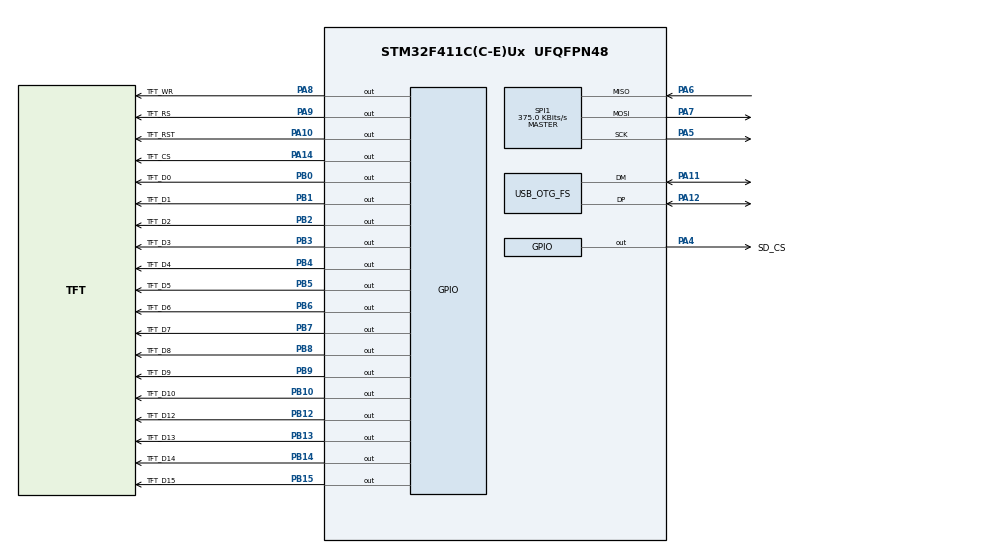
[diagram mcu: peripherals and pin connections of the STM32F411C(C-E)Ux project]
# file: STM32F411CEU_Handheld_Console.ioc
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ADC1.Channel-0\#ChannelRegularConversion=ADC_CHANNEL_VREFINT
ADC1.ClockPrescaler=ADC_CLOCK_SYNC_PCLK_DIV4
ADC1.NbrOfConversionFlag=1
ADC1.Rank-0\#ChannelRegularConversion=1
ADC1.SamplingTime-0\#ChannelRegularConversion=ADC_SAMPLETIME_3CYCLES
ADC1.master=1
Mcu.Family=STM32F4
Mcu.Name=STM32F411C(C-E)Ux
Mcu.Package=UFQFPN48
NVIC.OTG_FS_IRQn=true\:0\:0\:false\:false\:true\:false\:true\:true
NVIC.PriorityGroup=NVIC_PRIORITYGROUP_4
PA10.GPIO_Label=TFT_RST
PA10.GPIO_PuPd=GPIO_PULLDOWN
PA10.GPIO_Speed=GPIO_SPEED_FREQ_VERY_HIGH
PA10.Signal=GPIO_Output
PA11.Mode=Device_Only
PA11.Signal=USB_OTG_FS_DM
PA12.Mode=Device_Only
PA12.Signal=USB_OTG_FS_DP
PA14.GPIO_Label=TFT_CS
PA14.GPIO_PuPd=GPIO_PULLDOWN
PA14.GPIO_Speed=GPIO_SPEED_FREQ_VERY_HIGH
PA14.Signal=GPIO_Output
PA4.GPIO_Label=SD_CS
PA4.GPIO_Speed=GPIO_SPEED_FREQ_LOW
PA4.PinState=GPIO_PIN_RESET
PA4.Signal=GPIO_Output
PA5.GPIO_PuPd=GPIO_NOPULL
PA5.Mode=Full_Duplex_Master
PA5.Signal=SPI1_SCK
PA6.GPIO_PuPd=GPIO_NOPULL
PA6.Mode=Full_Duplex_Master
PA6.Signal=SPI1_MISO
PA7.GPIO_PuPd=GPIO_NOPULL
PA7.Mode=Full_Duplex_Master
PA7.Signal=SPI1_MOSI
PA8.GPIO_Label=TFT_WR
PA8.GPIO_PuPd=GPIO_PULLDOWN
PA8.GPIO_Speed=GPIO_SPEED_FREQ_VERY_HIGH
PA8.Signal=GPIO_Output
PA9.GPIO_Label=TFT_RS
PA9.GPIO_PuPd=GPIO_PULLDOWN
PA9.GPIO_Speed=GPIO_SPEED_FREQ_VERY_HIGH
PA9.Signal=GPIO_Output
PB0.GPIO_Label=TFT_D0
PB0.GPIO_PuPd=GPIO_PULLDOWN
PB0.GPIO_Speed=GPIO_SPEED_FREQ_VERY_HIGH
PB0.Signal=GPIO_Output
PB1.GPIO_Label=TFT_D1
PB1.GPIO_PuPd=GPIO_PULLDOWN
PB1.GPIO_Speed=GPIO_SPEED_FREQ_VERY_HIGH
PB1.Signal=GPIO_Output
PB10.GPIO_Label=TFT_D10
PB10.GPIO_PuPd=GPIO_PULLDOWN
PB10.GPIO_Speed=GPIO_SPEED_FREQ_VERY_HIGH
PB10.Signal=GPIO_Output
PB12.GPIO_Label=TFT_D12
PB12.GPIO_PuPd=GPIO_PULLDOWN
PB12.GPIO_Speed=GPIO_SPEED_FREQ_VERY_HIGH
PB12.Signal=GPIO_Output
PB13.GPIO_Label=TFT_D13
PB13.GPIO_PuPd=GPIO_PULLDOWN
PB13.GPIO_Speed=GPIO_SPEED_FREQ_VERY_HIGH
PB13.Signal=GPIO_Output
PB14.GPIO_Label=TFT_D14
PB14.GPIO_PuPd=GPIO_PULLDOWN
PB14.GPIO_Speed=GPIO_SPEED_FREQ_VERY_HIGH
PB14.Signal=GPIO_Output
PB15.GPIO_Label=TFT_D15
PB15.GPIO_PuPd=GPIO_PULLDOWN
PB15.GPIO_Speed=GPIO_SPEED_FREQ_VERY_HIGH
PB15.Signal=GPIO_Output
PB2.GPIO_Label=TFT_D2
PB2.GPIO_PuPd=GPIO_PULLDOWN
PB2.GPIO_Speed=GPIO_SPEED_FREQ_VERY_HIGH
PB2.Signal=GPIO_Output
PB3.GPIO_Label=TFT_D3
PB3.GPIO_PuPd=GPIO_PULLDOWN
PB3.GPIO_Speed=GPIO_SPEED_FREQ_VERY_HIGH
PB3.Signal=GPIO_Output
PB4.GPIO_Label=TFT_D4
PB4.GPIO_PuPd=GPIO_PULLDOWN
PB4.GPIO_Speed=GPIO_SPEED_FREQ_VERY_HIGH
PB4.Signal=GPIO_Output
PB5.GPIO_Label=TFT_D5
PB5.GPIO_PuPd=GPIO_PULLDOWN
PB5.GPIO_Speed=GPIO_SPEED_FREQ_VERY_HIGH
PB5.Signal=GPIO_Output
PB6.GPIO_Label=TFT_D6
PB6.GPIO_PuPd=GPIO_PULLDOWN
PB6.GPIO_Speed=GPIO_SPEED_FREQ_VERY_HIGH
PB6.Signal=GPIO_Output
PB7.GPIO_Label=TFT_D7
PB7.GPIO_PuPd=GPIO_PULLDOWN
PB7.GPIO_Speed=GPIO_SPEED_FREQ_VERY_HIGH
PB7.Signal=GPIO_Output
PB8.GPIO_Label=TFT_D8
PB8.GPIO_PuPd=GPIO_PULLDOWN
PB8.GPIO_Speed=GPIO_SPEED_FREQ_VERY_HIGH
PB8.Signal=GPIO_Output
PB9.GPIO_Label=TFT_D9
PB9.GPIO_PuPd=GPIO_PULLDOWN
PB9.GPIO_Speed=GPIO_SPEED_FREQ_VERY_HIGH
PB9.Signal=GPIO_Output
PH0\ -\ OSC_IN.Mode=HSE-External-Oscillator
PH0\ -\ OSC_IN.Signal=RCC_OSC_IN
PH1\ -\ OSC_OUT.Mode=HSE-External-Oscillator
PH1\ -\ OSC_OUT.Signal=RCC_OSC_OUT
ProjectManager.HeapSize=0x200
ProjectManager.StackSize=0x400
ProjectManager.TargetToolchain=STM32CubeIDE
RCC.48MHZClocksFreq_Value=48000000
RCC.AHBFreq_Value=96000000
RCC.APB1CLKDivider=RCC_HCLK_DIV2
RCC.APB1Freq_Value=48000000
RCC.APB1TimFreq_Value=96000000
RCC.APB2Freq_Value=96000000
RCC.APB2TimFreq_Value=96000000
RCC.CortexFreq_Value=96000000
RCC.HCLKFreq_Value=96000000
RCC.HSE_VALUE=25000000
RCC.HSI_VALUE=16000000
RCC.LSE_VALUE=32768
RCC.PLLM=25
RCC.SYSCLKFreq_VALUE=96000000
RCC.SYSCLKSource=RCC_SYSCLKSOURCE_PLLCLK
RCC.VCOOutputFreq_Value=192000000
SPI1.BaudRatePrescaler=SPI_BAUDRATEPRESCALER_256
SPI1.CLKPolarity=SPI_POLARITY_LOW
SPI1.CRCCalculation=SPI_CRCCALCULATION_DISABLE
SPI1.CalculateBaudRate=375.0 KBits/s
SPI1.Direction=SPI_DIRECTION_2LINES
SPI1.FirstBit=SPI_FIRSTBIT_MSB
SPI1.Mode=SPI_MODE_MASTER
SPI1.VirtualType=VM_MASTER
USB_DEVICE.CLASS_NAME_FS=CDC
USB_DEVICE.VirtualMode=Cdc
USB_DEVICE.VirtualModeFS=Cdc_FS
USB_OTG_FS.VirtualMode=Device_Only
VP_ADC1_Vref_Input.Mode=IN-Vrefint
VP_FATFS_VS_Generic.Mode=User_defined
VP_USB_DEVICE_VS_USB_DEVICE_CDC_FS.Mode=CDC_FS
board=custom

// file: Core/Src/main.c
/* USER CODE BEGIN Header */
/**
 ******************************************************************************
 * @file           : main.c
 * @brief          : Main program body
 ******************************************************************************
 * @attention
 *
 * Copyright (c) 2023 STMicroelectronics.
 * All rights reserved.
 *
 * This software is licensed under terms that can be found in the LICENSE file
 * in the root directory of this software component.
 * If no LICENSE file comes with this software, it is provided AS-IS.
 *
 ******************************************************************************
 */
/* USER CODE END Header */
#include "main.h"
#include "fatfs.h"

/* USER CODE BEGIN Includes */
#include "../STM32_Handheld_Console/STM32_Handheld_Console.h"
/* USER CODE END Includes */

ADC_HandleTypeDef hadc1;

SPI_HandleTypeDef hspi1;

void SystemClock_Config(void);
static void MX_GPIO_Init(void);
static void MX_SPI1_Init(void);
static void MX_ADC1_Init(void);

int main(void)
{

  /* MCU Configuration--------------------------------------------------------*/

  /* Reset of all peripherals, Initializes the Flash interface and the Systick. */
  HAL_Init();

  /* Configure the system clock */
  SystemClock_Config();

  /* Initialize all configured peripherals */
  MX_GPIO_Init();
  MX_SPI1_Init();
  MX_FATFS_Init();
  MX_ADC1_Init();
  /* USER CODE BEGIN 2 */
  system_main();
  /* USER CODE END 2 */

  /* Infinite loop */
	while (1)
	{

	}
}

void SystemClock_Config(void)
{
  RCC_OscInitTypeDef RCC_OscInitStruct = {0};
  RCC_ClkInitTypeDef RCC_ClkInitStruct = {0};

  /** Configure the main internal regulator output voltage
  */
  __HAL_RCC_PWR_CLK_ENABLE();
  __HAL_PWR_VOLTAGESCALING_CONFIG(PWR_REGULATOR_VOLTAGE_SCALE1);

  /** Initializes the RCC Oscillators according to the specified parameters
  * in the RCC_OscInitTypeDef structure.
  */
  RCC_OscInitStruct.OscillatorType = RCC_OSCILLATORTYPE_HSE;
  RCC_OscInitStruct.HSEState = RCC_HSE_ON;
  RCC_OscInitStruct.PLL.PLLState = RCC_PLL_ON;
  RCC_OscInitStruct.PLL.PLLSource = RCC_PLLSOURCE_HSE;
  RCC_OscInitStruct.PLL.PLLM = 12;
  RCC_OscInitStruct.PLL.PLLN = 96;
  RCC_OscInitStruct.PLL.PLLP = RCC_PLLP_DIV2;
  RCC_OscInitStruct.PLL.PLLQ = 4;
  if (HAL_RCC_OscConfig(&RCC_OscInitStruct) != HAL_OK)
  {
    Error_Handler();
  }

  /** Initializes the CPU, AHB and APB buses clocks
  */
  RCC_ClkInitStruct.ClockType = RCC_CLOCKTYPE_HCLK|RCC_CLOCKTYPE_SYSCLK
                              |RCC_CLOCKTYPE_PCLK1|RCC_CLOCKTYPE_PCLK2;
  RCC_ClkInitStruct.SYSCLKSource = RCC_SYSCLKSOURCE_PLLCLK;
  RCC_ClkInitStruct.AHBCLKDivider = RCC_SYSCLK_DIV1;
  RCC_ClkInitStruct.APB1CLKDivider = RCC_HCLK_DIV2;
  RCC_ClkInitStruct.APB2CLKDivider = RCC_HCLK_DIV1;

  if (HAL_RCC_ClockConfig(&RCC_ClkInitStruct, FLASH_LATENCY_3) != HAL_OK)
  {
    Error_Handler();
  }
}

static void MX_ADC1_Init(void)
{

  ADC_ChannelConfTypeDef sConfig = {0};

  /** Configure the global features of the ADC (Clock, Resolution, Data Alignment and number of conversion)
  */
  hadc1.Instance = ADC1;
  hadc1.Init.ClockPrescaler = ADC_CLOCK_SYNC_PCLK_DIV4;
  hadc1.Init.Resolution = ADC_RESOLUTION_12B;
  hadc1.Init.ScanConvMode = DISABLE;
  hadc1.Init.ContinuousConvMode = DISABLE;
  hadc1.Init.DiscontinuousConvMode = DISABLE;
  hadc1.Init.ExternalTrigConvEdge = ADC_EXTERNALTRIGCONVEDGE_NONE;
  hadc1.Init.ExternalTrigConv = ADC_SOFTWARE_START;
  hadc1.Init.DataAlign = ADC_DATAALIGN_RIGHT;
  hadc1.Init.NbrOfConversion = 1;
  hadc1.Init.DMAContinuousRequests = DISABLE;
  hadc1.Init.EOCSelection = ADC_EOC_SINGLE_CONV;
  if (HAL_ADC_Init(&hadc1) != HAL_OK)
  {
    Error_Handler();
  }

  /** Configure for the selected ADC regular channel its corresponding rank in the sequencer and its sample time.
  */
  sConfig.Channel = ADC_CHANNEL_VREFINT;
  sConfig.Rank = 1;
  sConfig.SamplingTime = ADC_SAMPLETIME_3CYCLES;
  if (HAL_ADC_ConfigChannel(&hadc1, &sConfig) != HAL_OK)
  {
    Error_Handler();
  }

}

static void MX_SPI1_Init(void)
{

  /* SPI1 parameter configuration*/
  hspi1.Instance = SPI1;
  hspi1.Init.Mode = SPI_MODE_MASTER;
  hspi1.Init.Direction = SPI_DIRECTION_2LINES;
  hspi1.Init.DataSize = SPI_DATASIZE_8BIT;
  hspi1.Init.CLKPolarity = SPI_POLARITY_LOW;
  hspi1.Init.CLKPhase = SPI_PHASE_1EDGE;
  hspi1.Init.NSS = SPI_NSS_SOFT;
  hspi1.Init.BaudRatePrescaler = SPI_BAUDRATEPRESCALER_256;
  hspi1.Init.FirstBit = SPI_FIRSTBIT_MSB;
  hspi1.Init.TIMode = SPI_TIMODE_DISABLE;
  hspi1.Init.CRCCalculation = SPI_CRCCALCULATION_DISABLE;
  hspi1.Init.CRCPolynomial = 10;
  if (HAL_SPI_Init(&hspi1) != HAL_OK)
  {
    Error_Handler();
  }

}

static void MX_GPIO_Init(void)
{
  GPIO_InitTypeDef GPIO_InitStruct = {0};

  /* GPIO Ports Clock Enable */
  __HAL_RCC_GPIOH_CLK_ENABLE();
  __HAL_RCC_GPIOA_CLK_ENABLE();
  __HAL_RCC_GPIOB_CLK_ENABLE();

  /*Configure GPIO pin Output Level */
  HAL_GPIO_WritePin(GPIOA, SD_CS_Pin|TFT_WR_Pin|TFT_RS_Pin|TFT_RST_Pin
                          |TFT_CS_Pin, GPIO_PIN_RESET);

  /*Configure GPIO pin Output Level */
  HAL_GPIO_WritePin(GPIOB, TFT_D0_Pin|TFT_D1_Pin|TFT_D2_Pin|TFT_D10_Pin
                          |TFT_D12_Pin|TFT_D13_Pin|TFT_D14_Pin|TFT_D15_Pin
                          |TFT_D3_Pin|TFT_D4_Pin|TFT_D5_Pin|TFT_D6_Pin
                          |TFT_D7_Pin|TFT_D8_Pin|TFT_D9_Pin, GPIO_PIN_RESET);

  /*Configure GPIO pin : SD_CS_Pin */
  GPIO_InitStruct.Pin = SD_CS_Pin;
  GPIO_InitStruct.Mode = GPIO_MODE_OUTPUT_PP;
  GPIO_InitStruct.Pull = GPIO_NOPULL;
  GPIO_InitStruct.Speed = GPIO_SPEED_FREQ_LOW;
  HAL_GPIO_Init(SD_CS_GPIO_Port, &GPIO_InitStruct);

  /*Configure GPIO pins : TFT_D0_Pin TFT_D1_Pin TFT_D2_Pin TFT_D10_Pin
                           TFT_D12_Pin TFT_D13_Pin TFT_D14_Pin TFT_D15_Pin
                           TFT_D3_Pin TFT_D4_Pin TFT_D5_Pin TFT_D6_Pin
                           TFT_D7_Pin TFT_D8_Pin TFT_D9_Pin */
  GPIO_InitStruct.Pin = TFT_D0_Pin|TFT_D1_Pin|TFT_D2_Pin|TFT_D10_Pin
                          |TFT_D12_Pin|TFT_D13_Pin|TFT_D14_Pin|TFT_D15_Pin
                          |TFT_D3_Pin|TFT_D4_Pin|TFT_D5_Pin|TFT_D6_Pin
                          |TFT_D7_Pin|TFT_D8_Pin|TFT_D9_Pin;
  GPIO_InitStruct.Mode = GPIO_MODE_OUTPUT_PP;
  GPIO_InitStruct.Pull = GPIO_PULLDOWN;
  GPIO_InitStruct.Speed = GPIO_SPEED_FREQ_VERY_HIGH;
  HAL_GPIO_Init(GPIOB, &GPIO_InitStruct);

  /*Configure GPIO pins : TFT_WR_Pin TFT_RS_Pin TFT_RST_Pin TFT_CS_Pin */
  GPIO_InitStruct.Pin = TFT_WR_Pin|TFT_RS_Pin|TFT_RST_Pin|TFT_CS_Pin;
  GPIO_InitStruct.Mode = GPIO_MODE_OUTPUT_PP;
  GPIO_InitStruct.Pull = GPIO_PULLDOWN;
  GPIO_InitStruct.Speed = GPIO_SPEED_FREQ_VERY_HIGH;
  HAL_GPIO_Init(GPIOA, &GPIO_InitStruct);

  /*Configure GPIO pin : INPUT_EN_Pin */
  GPIO_InitStruct.Pin = INPUT_EN_Pin;
  GPIO_InitStruct.Mode = GPIO_MODE_INPUT;
  GPIO_InitStruct.Pull = GPIO_NOPULL;
  HAL_GPIO_Init(INPUT_EN_GPIO_Port, &GPIO_InitStruct);

}

void Error_Handler(void)
{
	__disable_irq();
	while (1) {
	}
}
